VERSION 5.7 ;
  NOWIREEXTENSIONATPIN ON ;
  DIVIDERCHAR "/" ;
  BUSBITCHARS "[]" ;
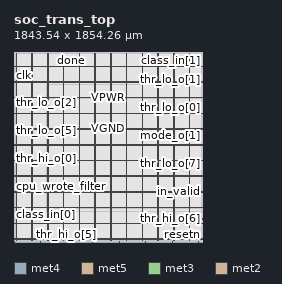
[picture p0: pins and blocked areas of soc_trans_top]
MACRO soc_trans_top
  CLASS BLOCK ;
  FOREIGN soc_trans_top ;
  ORIGIN 0.000 0.000 ;
  SIZE 1843.540 BY 1854.260 ;
  PIN VGND
    DIRECTION INOUT ;
    USE GROUND ;
    PORT
      LAYER met4 ;
        RECT 24.340 10.640 25.940 1841.680 ;
    END
    PORT
      LAYER met4 ;
        RECT 177.940 10.640 179.540 1841.680 ;
    END
    PORT
      LAYER met4 ;
        RECT 331.540 10.640 333.140 1841.680 ;
    END
    PORT
      LAYER met4 ;
        RECT 485.140 10.640 486.740 1841.680 ;
    END
    PORT
      LAYER met4 ;
        RECT 638.740 10.640 640.340 1841.680 ;
    END
    PORT
      LAYER met4 ;
        RECT 792.340 10.640 793.940 1841.680 ;
    END
    PORT
      LAYER met4 ;
        RECT 945.940 10.640 947.540 1841.680 ;
    END
    PORT
      LAYER met4 ;
        RECT 1099.540 10.640 1101.140 1841.680 ;
    END
    PORT
      LAYER met4 ;
        RECT 1253.140 10.640 1254.740 1841.680 ;
    END
    PORT
      LAYER met4 ;
        RECT 1406.740 10.640 1408.340 1841.680 ;
    END
    PORT
      LAYER met4 ;
        RECT 1560.340 10.640 1561.940 1841.680 ;
    END
    PORT
      LAYER met4 ;
        RECT 1713.940 10.640 1715.540 1841.680 ;
    END
    PORT
      LAYER met5 ;
        RECT 5.280 30.030 1837.940 31.630 ;
    END
    PORT
      LAYER met5 ;
        RECT 5.280 183.210 1837.940 184.810 ;
    END
    PORT
      LAYER met5 ;
        RECT 5.280 336.390 1837.940 337.990 ;
    END
    PORT
      LAYER met5 ;
        RECT 5.280 489.570 1837.940 491.170 ;
    END
    PORT
      LAYER met5 ;
        RECT 5.280 642.750 1837.940 644.350 ;
    END
    PORT
      LAYER met5 ;
        RECT 5.280 795.930 1837.940 797.530 ;
    END
    PORT
      LAYER met5 ;
        RECT 5.280 949.110 1837.940 950.710 ;
    END
    PORT
      LAYER met5 ;
        RECT 5.280 1102.290 1837.940 1103.890 ;
    END
    PORT
      LAYER met5 ;
        RECT 5.280 1255.470 1837.940 1257.070 ;
    END
    PORT
      LAYER met5 ;
        RECT 5.280 1408.650 1837.940 1410.250 ;
    END
    PORT
      LAYER met5 ;
        RECT 5.280 1561.830 1837.940 1563.430 ;
    END
    PORT
      LAYER met5 ;
        RECT 5.280 1715.010 1837.940 1716.610 ;
    END
  END VGND
  PIN VPWR
    DIRECTION INOUT ;
    USE POWER ;
    PORT
      LAYER met4 ;
        RECT 21.040 10.640 22.640 1841.680 ;
    END
    PORT
      LAYER met4 ;
        RECT 174.640 10.640 176.240 1841.680 ;
    END
    PORT
      LAYER met4 ;
        RECT 328.240 10.640 329.840 1841.680 ;
    END
    PORT
      LAYER met4 ;
        RECT 481.840 10.640 483.440 1841.680 ;
    END
    PORT
      LAYER met4 ;
        RECT 635.440 10.640 637.040 1841.680 ;
    END
    PORT
      LAYER met4 ;
        RECT 789.040 10.640 790.640 1841.680 ;
    END
    PORT
      LAYER met4 ;
        RECT 942.640 10.640 944.240 1841.680 ;
    END
    PORT
      LAYER met4 ;
        RECT 1096.240 10.640 1097.840 1841.680 ;
    END
    PORT
      LAYER met4 ;
        RECT 1249.840 10.640 1251.440 1841.680 ;
    END
    PORT
      LAYER met4 ;
        RECT 1403.440 10.640 1405.040 1841.680 ;
    END
    PORT
      LAYER met4 ;
        RECT 1557.040 10.640 1558.640 1841.680 ;
    END
    PORT
      LAYER met4 ;
        RECT 1710.640 10.640 1712.240 1841.680 ;
    END
    PORT
      LAYER met5 ;
        RECT 5.280 26.730 1837.940 28.330 ;
    END
    PORT
      LAYER met5 ;
        RECT 5.280 179.910 1837.940 181.510 ;
    END
    PORT
      LAYER met5 ;
        RECT 5.280 333.090 1837.940 334.690 ;
    END
    PORT
      LAYER met5 ;
        RECT 5.280 486.270 1837.940 487.870 ;
    END
    PORT
      LAYER met5 ;
        RECT 5.280 639.450 1837.940 641.050 ;
    END
    PORT
      LAYER met5 ;
        RECT 5.280 792.630 1837.940 794.230 ;
    END
    PORT
      LAYER met5 ;
        RECT 5.280 945.810 1837.940 947.410 ;
    END
    PORT
      LAYER met5 ;
        RECT 5.280 1098.990 1837.940 1100.590 ;
    END
    PORT
      LAYER met5 ;
        RECT 5.280 1252.170 1837.940 1253.770 ;
    END
    PORT
      LAYER met5 ;
        RECT 5.280 1405.350 1837.940 1406.950 ;
    END
    PORT
      LAYER met5 ;
        RECT 5.280 1558.530 1837.940 1560.130 ;
    END
    PORT
      LAYER met5 ;
        RECT 5.280 1711.710 1837.940 1713.310 ;
    END
  END VPWR
  PIN class_in[0]
    DIRECTION INPUT ;
    USE SIGNAL ;
    ANTENNAGATEAREA 0.990000 ;
    PORT
      LAYER met3 ;
        RECT 0.000 268.640 4.000 269.240 ;
    END
  END class_in[0]
  PIN class_in[1]
    DIRECTION INPUT ;
    USE SIGNAL ;
    ANTENNAGATEAREA 0.495000 ;
    PORT
      LAYER met2 ;
        RECT 1841.930 1850.260 1842.210 1854.260 ;
    END
  END class_in[1]
  PIN clk
    DIRECTION INPUT ;
    USE SIGNAL ;
    ANTENNAGATEAREA 1.286700 ;
    ANTENNADIFFAREA 0.434700 ;
    PORT
      LAYER met3 ;
        RECT 0.000 1628.640 4.000 1629.240 ;
    END
  END clk
  PIN cpu_wrote_filter
    DIRECTION OUTPUT TRISTATE ;
    USE SIGNAL ;
    ANTENNADIFFAREA 0.795200 ;
    PORT
      LAYER met3 ;
        RECT 0.000 540.640 4.000 541.240 ;
    END
  END cpu_wrote_filter
  PIN done
    DIRECTION OUTPUT TRISTATE ;
    USE SIGNAL ;
    ANTENNADIFFAREA 0.795200 ;
    PORT
      LAYER met2 ;
        RECT 557.150 1850.260 557.430 1854.260 ;
    END
  END done
  PIN edge_out
    DIRECTION OUTPUT TRISTATE ;
    USE SIGNAL ;
    ANTENNADIFFAREA 0.795200 ;
    PORT
      LAYER met2 ;
        RECT 814.750 1850.260 815.030 1854.260 ;
    END
  END edge_out
  PIN in_valid
    DIRECTION INPUT ;
    USE SIGNAL ;
    ANTENNAGATEAREA 0.990000 ;
    PORT
      LAYER met3 ;
        RECT 1839.540 496.440 1843.540 497.040 ;
    END
  END in_valid
  PIN load_ready
    DIRECTION OUTPUT TRISTATE ;
    USE SIGNAL ;
    ANTENNADIFFAREA 0.795200 ;
    PORT
      LAYER met2 ;
        RECT 1587.550 1850.260 1587.830 1854.260 ;
    END
  END load_ready
  PIN mode_o[0]
    DIRECTION OUTPUT TRISTATE ;
    USE SIGNAL ;
    ANTENNADIFFAREA 0.795200 ;
    PORT
      LAYER met2 ;
        RECT 1284.870 0.000 1285.150 4.000 ;
    END
  END mode_o[0]
  PIN mode_o[1]
    DIRECTION OUTPUT TRISTATE ;
    USE SIGNAL ;
    ANTENNADIFFAREA 0.795200 ;
    PORT
      LAYER met3 ;
        RECT 1839.540 1040.440 1843.540 1041.040 ;
    END
  END mode_o[1]
  PIN out_valid
    DIRECTION OUTPUT TRISTATE ;
    USE SIGNAL ;
    ANTENNADIFFAREA 0.795200 ;
    PORT
      LAYER met2 ;
        RECT 1329.950 1850.260 1330.230 1854.260 ;
    END
  END out_valid
  PIN resetn
    DIRECTION INPUT ;
    USE SIGNAL ;
    ANTENNAGATEAREA 0.990000 ;
    PORT
      LAYER met2 ;
        RECT 1800.070 0.000 1800.350 4.000 ;
    END
  END resetn
  PIN thr_hi_o[0]
    DIRECTION OUTPUT TRISTATE ;
    USE SIGNAL ;
    ANTENNADIFFAREA 0.795200 ;
    PORT
      LAYER met3 ;
        RECT 0.000 812.640 4.000 813.240 ;
    END
  END thr_hi_o[0]
  PIN thr_hi_o[1]
    DIRECTION OUTPUT TRISTATE ;
    USE SIGNAL ;
    ANTENNADIFFAREA 0.795200 ;
    PORT
      LAYER met2 ;
        RECT 299.550 1850.260 299.830 1854.260 ;
    END
  END thr_hi_o[1]
  PIN thr_hi_o[2]
    DIRECTION OUTPUT TRISTATE ;
    USE SIGNAL ;
    ANTENNADIFFAREA 0.795200 ;
    PORT
      LAYER met2 ;
        RECT 1542.470 0.000 1542.750 4.000 ;
    END
  END thr_hi_o[2]
  PIN thr_hi_o[3]
    DIRECTION OUTPUT TRISTATE ;
    USE SIGNAL ;
    ANTENNADIFFAREA 0.795200 ;
    PORT
      LAYER met2 ;
        RECT 0.090 0.000 0.370 4.000 ;
    END
  END thr_hi_o[3]
  PIN thr_hi_o[4]
    DIRECTION OUTPUT TRISTATE ;
    USE SIGNAL ;
    ANTENNADIFFAREA 0.795200 ;
    PORT
      LAYER met2 ;
        RECT 254.470 0.000 254.750 4.000 ;
    END
  END thr_hi_o[4]
  PIN thr_hi_o[5]
    DIRECTION OUTPUT TRISTATE ;
    USE SIGNAL ;
    ANTENNADIFFAREA 0.795200 ;
    PORT
      LAYER met2 ;
        RECT 512.070 0.000 512.350 4.000 ;
    END
  END thr_hi_o[5]
  PIN thr_hi_o[6]
    DIRECTION OUTPUT TRISTATE ;
    USE SIGNAL ;
    ANTENNADIFFAREA 0.795200 ;
    PORT
      LAYER met3 ;
        RECT 1839.540 224.440 1843.540 225.040 ;
    END
  END thr_hi_o[6]
  PIN thr_hi_o[7]
    DIRECTION OUTPUT TRISTATE ;
    USE SIGNAL ;
    ANTENNADIFFAREA 0.795200 ;
    PORT
      LAYER met2 ;
        RECT 769.670 0.000 769.950 4.000 ;
    END
  END thr_hi_o[7]
  PIN thr_lo_o[0]
    DIRECTION OUTPUT TRISTATE ;
    USE SIGNAL ;
    ANTENNADIFFAREA 0.795200 ;
    PORT
      LAYER met3 ;
        RECT 1839.540 1312.440 1843.540 1313.040 ;
    END
  END thr_lo_o[0]
  PIN thr_lo_o[1]
    DIRECTION OUTPUT TRISTATE ;
    USE SIGNAL ;
    ANTENNADIFFAREA 0.795200 ;
    PORT
      LAYER met3 ;
        RECT 1839.540 1584.440 1843.540 1585.040 ;
    END
  END thr_lo_o[1]
  PIN thr_lo_o[2]
    DIRECTION OUTPUT TRISTATE ;
    USE SIGNAL ;
    ANTENNADIFFAREA 0.795200 ;
    PORT
      LAYER met3 ;
        RECT 0.000 1356.640 4.000 1357.240 ;
    END
  END thr_lo_o[2]
  PIN thr_lo_o[3]
    DIRECTION OUTPUT TRISTATE ;
    USE SIGNAL ;
    ANTENNADIFFAREA 0.795200 ;
    PORT
      LAYER met2 ;
        RECT 1072.350 1850.260 1072.630 1854.260 ;
    END
  END thr_lo_o[3]
  PIN thr_lo_o[4]
    DIRECTION OUTPUT TRISTATE ;
    USE SIGNAL ;
    ANTENNADIFFAREA 0.795200 ;
    PORT
      LAYER met2 ;
        RECT 1027.270 0.000 1027.550 4.000 ;
    END
  END thr_lo_o[4]
  PIN thr_lo_o[5]
    DIRECTION OUTPUT TRISTATE ;
    USE SIGNAL ;
    ANTENNADIFFAREA 0.795200 ;
    PORT
      LAYER met3 ;
        RECT 0.000 1084.640 4.000 1085.240 ;
    END
  END thr_lo_o[5]
  PIN thr_lo_o[6]
    DIRECTION OUTPUT TRISTATE ;
    USE SIGNAL ;
    ANTENNADIFFAREA 0.795200 ;
    PORT
      LAYER met2 ;
        RECT 41.950 1850.260 42.230 1854.260 ;
    END
  END thr_lo_o[6]
  PIN thr_lo_o[7]
    DIRECTION OUTPUT TRISTATE ;
    USE SIGNAL ;
    ANTENNADIFFAREA 0.795200 ;
    PORT
      LAYER met3 ;
        RECT 1839.540 768.440 1843.540 769.040 ;
    END
  END thr_lo_o[7]
  OBS
      LAYER li1 ;
        RECT 5.520 10.795 1837.700 1841.525 ;
      LAYER met1 ;
        RECT 0.070 10.640 1842.230 1841.680 ;
      LAYER met2 ;
        RECT 0.100 1849.980 41.670 1850.260 ;
        RECT 42.510 1849.980 299.270 1850.260 ;
        RECT 300.110 1849.980 556.870 1850.260 ;
        RECT 557.710 1849.980 814.470 1850.260 ;
        RECT 815.310 1849.980 1072.070 1850.260 ;
        RECT 1072.910 1849.980 1329.670 1850.260 ;
        RECT 1330.510 1849.980 1587.270 1850.260 ;
        RECT 1588.110 1849.980 1841.650 1850.260 ;
        RECT 0.100 4.280 1842.200 1849.980 ;
        RECT 0.650 4.000 254.190 4.280 ;
        RECT 255.030 4.000 511.790 4.280 ;
        RECT 512.630 4.000 769.390 4.280 ;
        RECT 770.230 4.000 1026.990 4.280 ;
        RECT 1027.830 4.000 1284.590 4.280 ;
        RECT 1285.430 4.000 1542.190 4.280 ;
        RECT 1543.030 4.000 1799.790 4.280 ;
        RECT 1800.630 4.000 1842.200 4.280 ;
      LAYER met3 ;
        RECT 3.990 1629.640 1839.540 1841.605 ;
        RECT 4.400 1628.240 1839.540 1629.640 ;
        RECT 3.990 1585.440 1839.540 1628.240 ;
        RECT 3.990 1584.040 1839.140 1585.440 ;
        RECT 3.990 1357.640 1839.540 1584.040 ;
        RECT 4.400 1356.240 1839.540 1357.640 ;
        RECT 3.990 1313.440 1839.540 1356.240 ;
        RECT 3.990 1312.040 1839.140 1313.440 ;
        RECT 3.990 1085.640 1839.540 1312.040 ;
        RECT 4.400 1084.240 1839.540 1085.640 ;
        RECT 3.990 1041.440 1839.540 1084.240 ;
        RECT 3.990 1040.040 1839.140 1041.440 ;
        RECT 3.990 813.640 1839.540 1040.040 ;
        RECT 4.400 812.240 1839.540 813.640 ;
        RECT 3.990 769.440 1839.540 812.240 ;
        RECT 3.990 768.040 1839.140 769.440 ;
        RECT 3.990 541.640 1839.540 768.040 ;
        RECT 4.400 540.240 1839.540 541.640 ;
        RECT 3.990 497.440 1839.540 540.240 ;
        RECT 3.990 496.040 1839.140 497.440 ;
        RECT 3.990 269.640 1839.540 496.040 ;
        RECT 4.400 268.240 1839.540 269.640 ;
        RECT 3.990 225.440 1839.540 268.240 ;
        RECT 3.990 224.040 1839.140 225.440 ;
        RECT 3.990 10.715 1839.540 224.040 ;
      LAYER met4 ;
        RECT 16.855 19.895 20.640 1837.865 ;
        RECT 23.040 19.895 23.940 1837.865 ;
        RECT 26.340 19.895 174.240 1837.865 ;
        RECT 176.640 19.895 177.540 1837.865 ;
        RECT 179.940 19.895 327.840 1837.865 ;
        RECT 330.240 19.895 331.140 1837.865 ;
        RECT 333.540 19.895 481.440 1837.865 ;
        RECT 483.840 19.895 484.740 1837.865 ;
        RECT 487.140 19.895 635.040 1837.865 ;
        RECT 637.440 19.895 638.340 1837.865 ;
        RECT 640.740 19.895 788.640 1837.865 ;
        RECT 791.040 19.895 791.940 1837.865 ;
        RECT 794.340 19.895 942.240 1837.865 ;
        RECT 944.640 19.895 945.540 1837.865 ;
        RECT 947.940 19.895 1095.840 1837.865 ;
        RECT 1098.240 19.895 1099.140 1837.865 ;
        RECT 1101.540 19.895 1249.440 1837.865 ;
        RECT 1251.840 19.895 1252.740 1837.865 ;
        RECT 1255.140 19.895 1403.040 1837.865 ;
        RECT 1405.440 19.895 1406.340 1837.865 ;
        RECT 1408.740 19.895 1556.640 1837.865 ;
        RECT 1559.040 19.895 1559.940 1837.865 ;
        RECT 1562.340 19.895 1710.240 1837.865 ;
        RECT 1712.640 19.895 1713.540 1837.865 ;
        RECT 1715.940 19.895 1830.930 1837.865 ;
      LAYER met5 ;
        RECT 314.300 1411.850 1831.140 1539.300 ;
        RECT 314.300 1258.670 1831.140 1403.750 ;
        RECT 314.300 1105.490 1831.140 1250.570 ;
        RECT 314.300 952.310 1831.140 1097.390 ;
        RECT 314.300 799.130 1831.140 944.210 ;
        RECT 314.300 645.950 1831.140 791.030 ;
        RECT 314.300 492.770 1831.140 637.850 ;
        RECT 314.300 339.590 1831.140 484.670 ;
        RECT 314.300 293.300 1831.140 331.490 ;
  END
END soc_trans_top
END LIBRARY

